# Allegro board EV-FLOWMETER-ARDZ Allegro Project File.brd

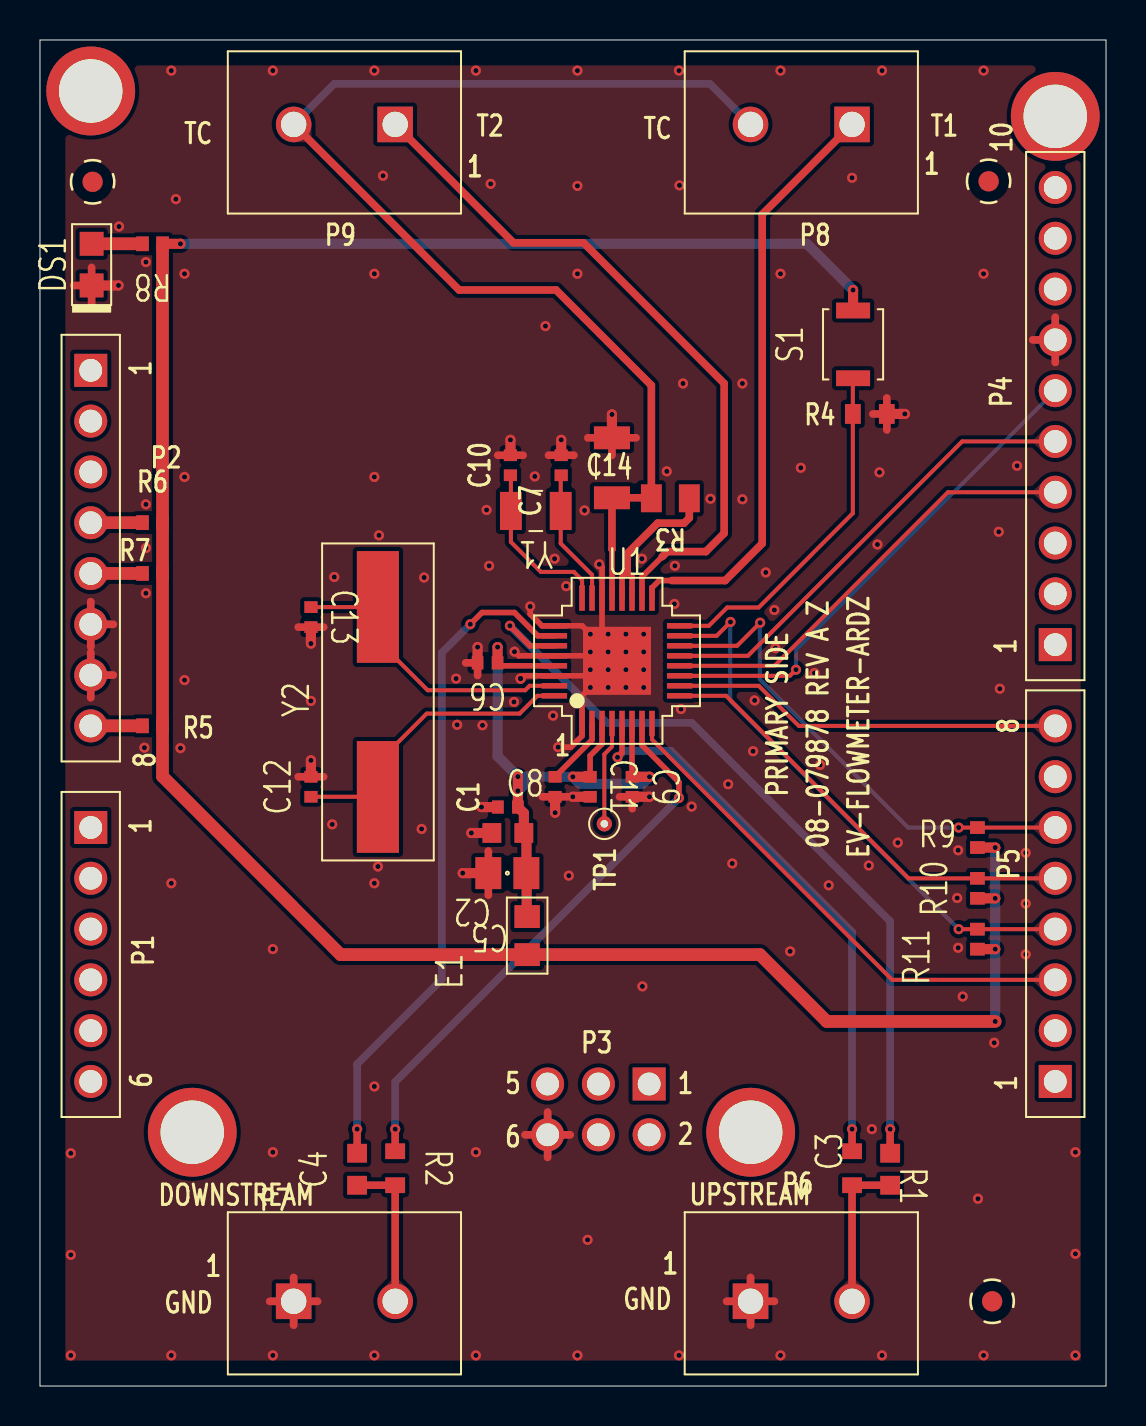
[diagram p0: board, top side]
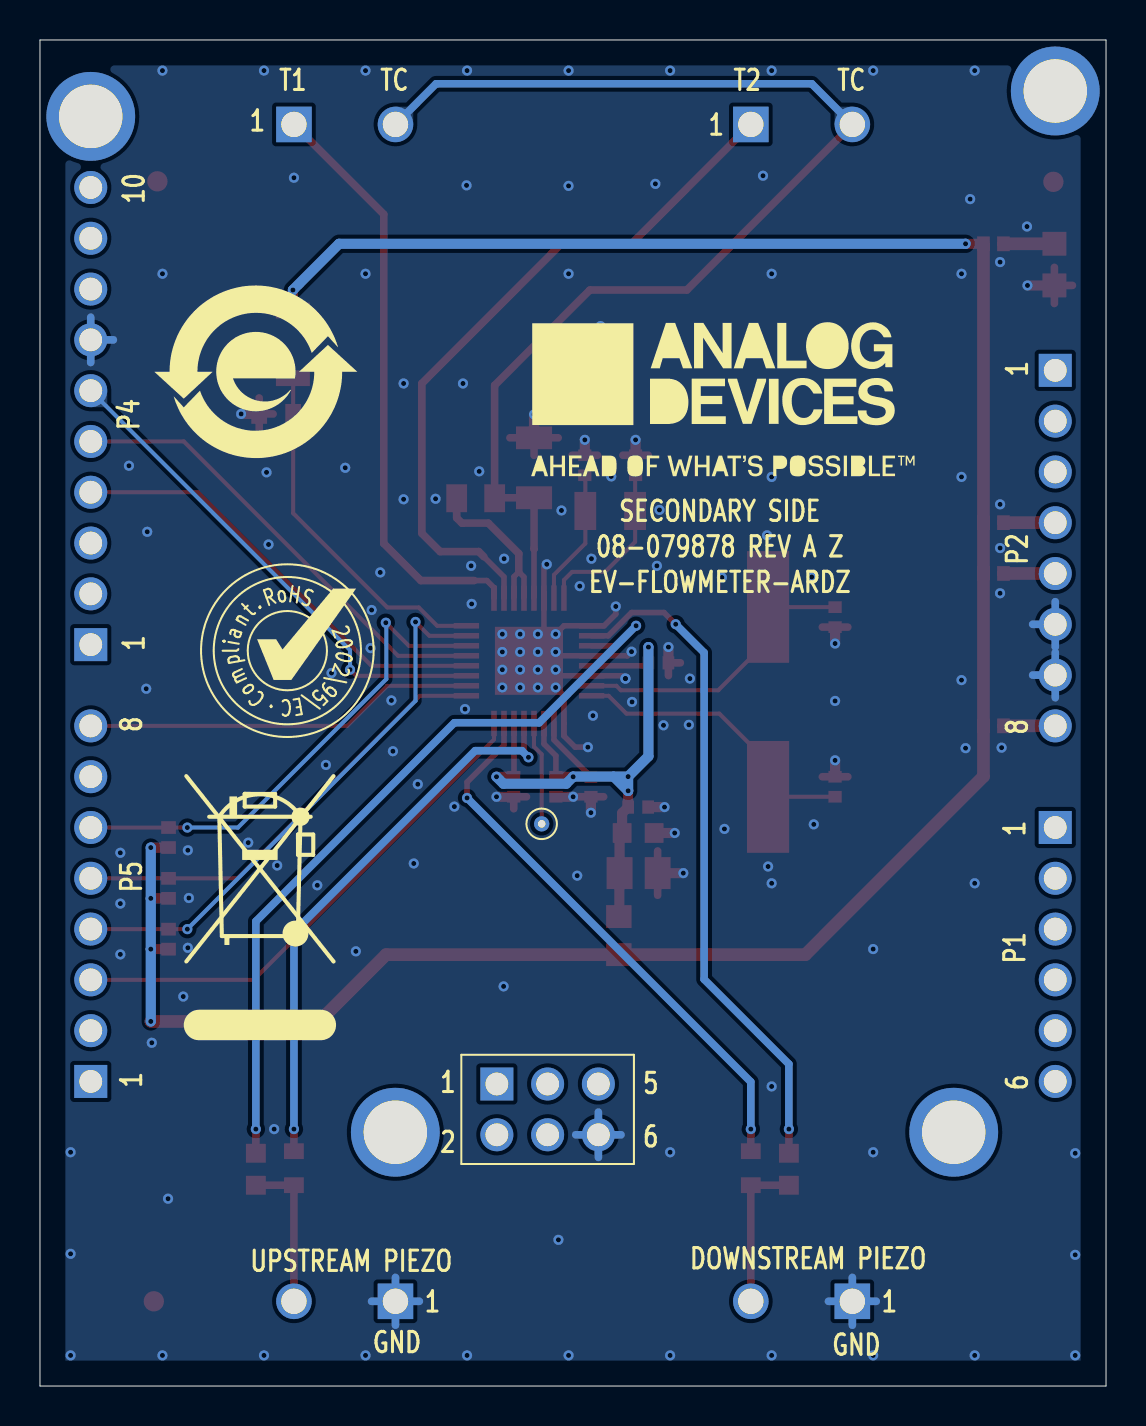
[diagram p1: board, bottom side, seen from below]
Outline 53.34 x 67.31 mm; copper layers: TOP, L2_GND, L3_GND, BOTTOM. Coordinates in mm from the lower left corner of the outline.
Outline path: 0,67.31 53.34,67.31 53.34,0 0,0 0,67.31

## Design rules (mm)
constraint set DEFAULT: min track width 0.203

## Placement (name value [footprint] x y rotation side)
C1  0.1uF  [C0402]  23.41 28.95 180 top
C2  2.2uF  [C0603]  23.41 27.65 180 top
C3  1000pF  [C0603]  42.54 10.84 90 top
C4  1000pF  [C0603]  15.87 10.84 90 top
C5  22UF  [C0805H60]  23.39 25.65 180 top
C6  0.1uF  [C0402]  22.4 36.16 180 top
C7  12pF  [C0402]  26.08 46.04 90 top
C8  0.1uF  [C0402]  25.77 29.97 90 top
C9  0.1uF  [C0402]  29.63 29.97 270 top
C10  12pF  [C0402]  23.54 46.04 90 top
C11  0.1uF  [C0402]  27.53 29.97 270 top
C12  12pF  [C0402]  13.56 29.97 90 top
C13  12pF  [C0402]  13.56 38.45 270 top
C14  0.1uF  [C1206]  28.62 45.92 90 top
DS1  SML-LXT0805YW-TR  [LXT0805]  2.58 56.08 90 top
E1  600OHM  [L0805H50]  24.38 22.52 90 top
NOREF  -  []  -14.58 90.73 0 top
NOREF#2  -  []  -30.49 -89.69 0 top
NOREF#3  -  [unnamed#2]  47.64 4.24 0 top
NOREF#4  -  [unnamed#2]  50.8 63.49 0 top
NOREF#5  -  []  -35.57 -94.77 0 top
NOREF#6  -  []  26.17 77.98 0 top
NOREF#7  -  []  -35.57 -94.77 0 top
NOREF#8  -  []  111.55 230.7 0 top
NOREF#9  -  [unnamed#2]  2.63 60.22 0 top
NOREF#10  -  []  -30.49 -89.69 0 top
NOREF#11  -  [unnamed#2]  35.56 12.69 0 top
NOREF#12  -  []  0 67.31 0 top
NOREF#13  -  [unnamed#2]  47.47 60.24 0 top
NOREF#14  -  []  100.54 -20.38 0 top
NOREF#15  -  []  53.34 0 90 top
NOREF#16  -  [unnamed#2]  2.54 64.76 0 top
NOREF#17  -  [unnamed#2]  7.62 12.69 0 top
NOREF#18  -  []  -35.57 -94.77 0 top
NOREF#19  -  []  19.14 49.32 180 bottom
NOREF#20  -  []  33.06 34.18 180 bottom
NOREF#21  -  []  40.96 36.77 180 bottom
NOREF#22  -  []  42.54 50.72 180 bottom
P1  SSQ-106-03-G-S  [CNSAMTECSSQ-106-XX-X-S]  2.54 27.93 270 top
P2  SSQ-108-03-G-S  [CNSAMTECSSQ-108-XX-X-S]  2.54 50.79 270 top
P3  SSQ-103-03-G-D  [CNSAMTECSSQ-103-XX-X-D]  30.48 15.1 180 bottom
P4  SSQ-110-03-G-S  [CNSAMTECSSQ-110-XX-X-S]  50.8 37.07 90 top
P5  SSQ-108-03-G-S  [CNSAMTECSSQ-108-XX-X-S]  50.8 15.23 90 top
P6  OSTTC022162  [CNHDR1X2H406]  35.55 4.24 0 top
P7  OSTTC022162  [CNHDR1X2H406]  12.69 4.24 0 top
P8  OSTTC022162  [CNHDR1X2H406]  40.63 63.09 180 top
P9  OSTTC022162  [CNHDR1X2H406]  17.77 63.09 180 top
R1  330  [R0603]  40.63 10.89 270 top
R2  330  [R0603]  17.77 10.89 270 top
R3  1K  [R0805]  31.54 44.39 180 top
R4  10MEG  [R0603]  41.52 48.61 0 top
R5  0  [R0402]  5.63 33.01 0 top
R6  0  [R0402]  5.63 43.17 0 top
R7  0  [R0402]  5.63 40.63 0 top
R8  470  [R0402]  5.63 57.12 180 top
R9  10K  [R0402]  46.91 27.43 90 top
R10  10K  [R0402]  46.91 24.89 90 top
R11  10K  [R0402]  46.91 22.35 90 top
S1  B3U-1000P  [SWSML118W98H69]  40.68 52.09 90 top
TP1  TESTPAD  [TPC30D15]  28.24 28.11 90 top
U1  MAX35101EHJ+  [QFP32_5X5_PAD3_4X3_4]  28.87 36.27 0 top
Y1  32.768KHZ  [YSML126W59H35]  24.81 43.76 180 top
Y2  4MEGHZ  [YSML450W190H160]  16.91 34.21 90 top

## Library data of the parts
C1 C6 C8 C9 C11 = CAP: User Part Number: UPN; Tolerance: 10; alternate symbols: (C0402); part number: CAP_SM-0.1UF,50V,10,E025746,C0402; tolerance: 10
C2 = CAP: User Part Number: UPN; Tolerance: 10; alternate symbols: (C0603); part number: CAP_SM-2.2UF,10V,10,E015288,C0603; tolerance: 10
C3 C4 = CAP: User Part Number: UPN; Tolerance: 1; alternate symbols: (C0603); part number: CAP_SM-1000PF,50V,1,E024659,C0603; tolerance: 1
C5 = CAP: Tolerance: 20; User Part Number: UPN; alternate symbols: (C0805H60); part number: CAP_SM-22UF,10V,20,E059803,C0805H60; tolerance: 20
C7 C10 C12 C13 = CAP: User Part Number: UPN; Tolerance: 5; alternate symbols: (C0402); part number: CAP_SM-12PF,50V,5,E033360,C0402; tolerance: 5
C14 = CAP: User Part Number: UPN; Tolerance: 2; alternate symbols: (C1206); part number: CAP_SM-0.1UF,25V,2,E012519,C1206; tolerance: 2
DS1 = DIOLED: Tolerance: N/A; User Part Number: UPN; alternate symbols: (LXT0805); part number: DIOLED_SM-SML-LXT0805YW-TR,N/A,N/A,E005351,LXT0805; tolerance: N/A
E1 = FERRITE: Tolerance: 25; User Part Number: UPN; alternate symbols: (L0805H50); part number: FERRITE_SM-600OHM,25,E013538,L0805H50; tolerance: 25
P1 = CN6P: User Part Number: UPN; Tolerance: N/A; alternate symbols: (CNSAMTECSSQ-106-XX-X-S); part number: CN6P_TH-SSQ-106-03-G-S,E020477,CNSAMTECSSQ-106-XX-X-S; tolerance: N/A
P2 P5 = CN8P_A: User Part Number: UPN; Tolerance: N/A; alternate symbols: (CNSAMTECSSQ-108-XX-X-S); part number: CN8P_A_TH-SSQ-108-03-G-S,E020478,CNSAMTECSSQ-108-XX-X-S; tolerance: N/A
P3 = CN6P_ODD_EVEN: User Part Number: UPN; Tolerance: N/A; alternate symbols: (CNSAMTECSSQ-103-XX-X-D); part number: CN6P_ODD_EVEN_TH-SSQ-103-03-G-D,E020488,CNSAMTECSSQ-103-XX-X-D; tolerance: N/A
P4 = CN10P: User Part Number: UPN; Tolerance: N/A; alternate symbols: (CNSAMTECSSQ-110-XX-X-S); part number: CN10P_TH-SSQ-110-03-G-S,E020479,CNSAMTECSSQ-110-XX-X-S; tolerance: N/A
P6-P9 = CN2P: User Part Number: UPN; Tolerance: N/A; alternate symbols: (CNHDR1X2H406); part number: CN2P_TH-OSTTC022162,E016936,CNHDR1X2H406; tolerance: N/A
R1 R2 = RES: User Part Number: UPN; Tolerance: 1; alternate symbols: (R0603); part number: RES_SM-330,E054284,1/10W,1,R0603; tolerance: 1
R3 = RES: User Part Number: UPN; Tolerance: 0.1; alternate symbols: (R0805); part number: RES_SM-1K,E003811,1/8W,0.1,R0805; tolerance: 0.1
R4 = RES: User Part Number: UPN; Tolerance: 1; alternate symbols: (R0603); part number: RES_SM-10MEG,E055939,1/10W,1,R0603; tolerance: 1
R5-R7 = RES: User Part Number: UPN; Tolerance: JUMPER; alternate symbols: (R0402); part number: RES_SM-0,E003438,1/10W,JUMPER,R0402; tolerance: JUMPER
R8 = RES: User Part Number: UPN; Tolerance: 1; alternate symbols: (R0402); part number: RES_SM-470,E014032,1/16W,1,R0402; tolerance: 1
R9-R11 = RES: User Part Number: UPN; Tolerance: 1; alternate symbols: (R0402); part number: RES_SM-10K,E003751,1/10W,1,R0402; tolerance: 1
S1 = SWSPST2PIN_V2: Tolerance: N/A; User Part Number: UPN; alternate symbols: (SWSML118W98H69); part number: SWSPST2PIN_V2_SM-B3U-1000P,E016303,SWSML118W98H69; tolerance: N/A
TP1 = NCTESTPAD: Tolerance: N/A; User Part Number: UPN; alternate symbols: (TPC30D15); part number: NCTESTPAD_TH-TESTPAD,E013464,TPC30D15; tolerance: N/A
U1 = ADMAX35101: User Part Number: UPN; Tolerance: N/A; alternate symbols: (QFP32_5X5_PAD3_4X3_4); part number: ADMAX35101_SM-MAX35101EHJ+,E062766,QFP32_5X5_PAD3_4X3_4; tolerance: N/A
Y1 = XTAL: User Part Number: UPN; Tolerance: N/A; alternate symbols: (YSML126W59H35); part number: XTAL_SM-32.768KHZ,E062517,YSML126W59H35; tolerance: N/A
Y2 = XTAL: Tolerance: 30PPM; User Part Number: UPN; alternate symbols: (YSML450W190H160); part number: XTAL_SM-4MEGHZ,E060056,YSML450W190H160; tolerance: 30PPM

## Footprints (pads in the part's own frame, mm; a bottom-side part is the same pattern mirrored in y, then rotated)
C0402
  rect 0.584x0.66 smd: 1(-0.5,0) 2(0.5,0)
C0603
  rect 0.94x0.991 smd: 1(-0.8,0) 2(0.8,0)
C0805H60
  rect 1.295x1.6 smd: 1(-0.953,0) 2(0.953,0)
C1206
  rect 1.143x1.803 smd: 1(-1.5,0) 2(1.5,0)
CNHDR1X2H406
  rect 1.778x1.778 hole 1.27: 1(0,0)
  round 1.778 hole 1.27: 2(5.08,0)
CNSAMTECSSQ-103-XX-X-D
  rect 1.651x1.651 hole 1.143: 1(0,0)
  round 1.651 hole 1.143: 2(0,-2.54) 3(2.54,0) 4(2.54,-2.54) 5(5.08,0) 6(5.08,-2.54)
CNSAMTECSSQ-106-XX-X-S
  rect 1.651x1.651 hole 1.143: 1(0,0)
  round 1.651 hole 1.143: 2(2.54,0) 3(5.08,0) 4(7.62,0) 5(10.16,0) 6(12.7,0)
CNSAMTECSSQ-108-XX-X-S
  rect 1.651x1.651 hole 1.143: 1(0,0)
  round 1.651 hole 1.143: 2(2.54,0) 3(5.08,0) 4(7.62,0) 5(10.16,0) 6(12.7,0) 7(15.24,0) 8(17.78,0)
CNSAMTECSSQ-110-XX-X-S
  rect 1.651x1.651 hole 1.143: 1(0,0)
  round 1.651 hole 1.143: 2(2.54,0) 3(5.08,0) 4(7.62,0) 5(10.16,0) 6(12.7,0) 7(15.24,0) 8(17.78,0) 9(20.32,0) 10(22.86,0)
L0805H50
  rect 1.143x1.27 smd: 1(-0.953,0) 2(0.953,0)
LXT0805
  rect 1.194x1.194 smd: A(1.041,0) C(-1.041,0)
QFP32_5X5_PAD3_4X3_4
  rect 0.279x1.27 smd: 1(-1.75,-3.134) 2(-1.25,-3.134) 3(-0.75,-3.134) 4(-0.25,-3.134) 5(0.25,-3.134) 6(0.75,-3.134) 7(1.25,-3.134) 8(1.75,-3.134) 17(1.75,3.134) 18(1.25,3.134) 19(0.75,3.134) 20(0.25,3.134) 21(-0.25,3.134) 22(-0.75,3.134) 23(-1.25,3.134) 24(-1.75,3.134)
  rect 1.27x0.279 smd: 9(3.134,-1.75) 10(3.134,-1.25) 11(3.134,-0.75) 12(3.134,-0.25) 13(3.134,0.25) 14(3.134,0.75) 15(3.134,1.25) 16(3.134,1.75) 25(-3.134,1.75) 26(-3.134,1.25) 27(-3.134,0.75) 28(-3.134,0.25) 29(-3.134,-0.25) 30(-3.134,-0.75) 31(-3.134,-1.25) 32(-3.134,-1.75)
  rect 3.404x3.404 smd: PAD(0,0)
R0402
  rect 0.635x0.737 smd: 1(-0.5,0) 2(0.5,0)
R0603
  rect 0.787x0.991 smd: 1(-0.85,0) 2(0.85,0)
R0805
  rect 1.041x1.397 smd: 1(-0.95,0) 2(0.95,0)
SWSML118W98H69
  rect 0.787x1.702 smd: 1(-1.694,0) 2(1.694,0)
TPC30D15
  round 0.762 hole 0.381: 1(0,0)
unnamed#2
  round 1.016 smd: (0,0)
YSML126W59H35
  rect 1.092x1.905 smd: 1(-1.246,0) 2(1.246,0)
YSML450W190H160
  rect 5.588x2.108 smd: 1(-4.75,0) 2(4.75,0)

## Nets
GND: C1.2(N2) C2.2(N2) C5.2(N2) C6.2(N2) C7.2(N2) C8.1 C9.2(N2) C10.2(N2) C11.2(N2) C12.2(N2) C13.2(N2) C14.2(N2) DS1.C P2.6 P2.7 P3.6(N6) P4.7 P6.1 P7.1 R4.2(N2) U1.1 U1.22 U1.25 U1.28 U1.30 U1.PAD
32KX0: C7.1 U1.23 Y1.1
32KX1: C10.1 U1.24 Y1.2(N2)
ARD_3V3: E1.1 R5.2(N2) R6.2(N2) R7.2(N2) R8.1 R9.1 R10.1 R11.1 S1.2(B)
ARD_CS: P5.8(N8) U1.10
ARD_MISO: P4.5 U1.13
ARD_MOSI: P4.4 U1.12
ARD_SCK: P4.6 U1.11
CMP_OUTPUT/UP_DN: P5.3 U1.8
CSW: R4.1 S1.1 U1.16
INT_N: P5.5 R10.2(N2) U1.9
LAUNCH_DN: R1.1 U1.5
LAUNCH_UP: R2.1 U1.7
RST_N: P5.6 R9.2(N2) U1.14
STOP_DN: C4.2(N2) U1.26
STOP_UP: C3.2(N2) U1.27
T1: P8.1 U1.17
T2: P9.1 U1.18
TC: C14.1 P8.2(N2) P9.2(N2) R3.2(N2) U1.21
UNNAMED_2_ADMAX35101_I1_32KOUT: TP1.1(N1) U1.4
UNNAMED_2_ADMAX35101_I1_BYPASS: C8.2(N2) U1.2
UNNAMED_2_ADMAX35101_I1_T3: R3.1 U1.19 U1.20
UNNAMED_2_CAP_I17_N1: C1.1 C2.1 C5.1 C6.1 C9.1 C11.1 E1.2(N2) U1.3 U1.6 U1.29
UNNAMED_2_CAP_I55_N1: C3.1 P6.2(N2) R1.2(N2)
UNNAMED_2_CAP_I59_N1: C4.1 P7.2(N2) R2.2(N2)
UNNAMED_2_CN8PA_I23_N4: P2.4 R6.1
UNNAMED_2_CN8PA_I23_N5: P2.5 R7.1
UNNAMED_2_CN8PA_I23_N8: P2.8(N8) R5.1
UNNAMED_2_DIOLED_I71_P: DS1.A(P) R8.2(N2)
WDO_N: P5.4 R11.2(N2) U1.15
X1: C12.1 U1.32 Y2.1
X2: C13.1 U1.31(X2) Y2.2(N2)

Pads without a net: P1 1 2 3 4 5 6; P2 1 2 3; P3 1 2 3 4 5; P4 1 2 3 8 9 10; P5 1 2 7

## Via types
v1: diameter 0.508, hole 0.254, TOP to BOTTOM, 172 vias

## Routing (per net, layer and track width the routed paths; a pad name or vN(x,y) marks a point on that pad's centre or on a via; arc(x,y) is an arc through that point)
GND: length 153.4
  TOP w0.279: v1(27.54,34.93) 27.12,34.52 U1.1 27.12,32.51 26.56,31.95 v1(25.93,31.95) ; v1(27.98,41.09) 28.12,40.95 U1.22 28.12,37.02 ; 28.62,36.52 U1.28 23.95,36.52 v1(23.74,36.72) ; 28.62,36.52 v1(28.43,36.71) 28.12,37.02 ; 28.62,36.52 U1.PAD v1(28.43,35.82) 28.12,35.52 U1.30 24.19,35.52 v1(24.05,35.38) ; v1(24.53,38.98) 24.53,38.6 25.12,38.02 U1.25 27.12,38.02 v1(27.54,37.6) 28.12,37.02
  TOP w0.381: 41.67,48.61 R4.2 ; R4.2 42.37,49.41 ; R4.2 42.37,47.81 ; 24.27,12.56 25.4,12.56 ; 25.4,12.56 26.53,12.56 ; 25.4,12.56 25.4,11.43 ; 25.4,12.56 25.4,13.69 ; 26.71,46.54 C7.2 25.44,46.54 ; 50.8,51.18 P4.7 ; P4.7 50.8,53.44 ; P4.7 49.67,52.31 ; DS1.C 2.58,55.94 ; DS1.C 2.58,54.13 ; DS1.C 1.68,55.04 ; 24.17,46.54 C10.2 22.9,46.54 ; 28.62,46.54 C14.2 ; C14.2 29.83,47.42 ; C14.2 27.41,47.42 ; 21.9,35.53 C6.2 21.3,36.16 ; P6.1 35.55,5.43 ; P6.1 35.55,3.04 ; P6.1 34.36,4.24 ; P6.1 36.75,4.24 ; 14.19,30.47 C12.2 12.92,30.47 ; 14.19,37.95 C13.2 12.92,37.95 ; P2.6 2.54,39.22 ; P2.6 3.67,38.09 ; P2.6 2.54,36.96 ; 22.43,26.75 C5.2 22.43,24.54 ; P7.1 13.89,4.24 ; P7.1 12.69,5.43 ; P7.1 12.69,3.04 ; P7.1 11.5,4.24 ; P2.7 3.67,35.55 ; P2.7 2.54,36.68 ; P2.7 2.54,34.42 ; 29.63,28.87 C9.2 29,29.47 ; 25.14,29.47 C8.1 26.41,29.47
  TOP w0.508: C7.2 v1(26.08,47.31) ; C5.2 v1(21.15,25.65) ; v1(43.27,48.61) R4.2 ; C11.2 v1(26.66,29.47) ; C8.1 v1(25.77,28.67) ; C1.2 v1(22.09,28.95) ; C9.2 v1(30.5,29.47) ; C14.2 v1(28.62,48.58) ; C13.2 v1(13.56,37.13) ; C2.2 v1(21.58,27.65) ; C6.2 v1(21.9,36.95) ; C10.2 v1(23.54,47.31) ; DS1.C v1(3.93,55.04) ; C12.2 v1(13.56,31.29)
  L2_GND w0.381: 12.69,3.04 P7.1 ; P7.1 13.89,4.24 ; P7.1 12.69,5.43 ; P7.1 11.5,4.24 ; P2.7 2.54,36.68 ; P2.7 2.54,34.42 ; P2.7 3.67,35.55 ; P2.6 2.54,39.22 ; P2.6 3.67,38.09 ; P2.6 2.54,36.96 ; 50.8,51.18 P4.7 ; P4.7 49.67,52.31 ; P4.7 50.8,53.44 ; 25.4,12.56 26.53,12.56 ; 25.4,12.56 25.4,11.43 ; 25.4,12.56 24.27,12.56 ; 25.4,12.56 25.4,13.69 ; P6.1 35.55,5.43 ; P6.1 36.75,4.24 ; P6.1 34.36,4.24 ; P6.1 35.55,3.04
  L3_GND w0.381: 11.5,4.24 P7.1 ; P7.1 13.89,4.24 ; P7.1 12.69,5.43 ; P7.1 12.69,3.04 ; P2.7 3.67,35.55 ; P2.7 2.54,34.42 ; P2.7 2.54,36.68 ; 2.54,36.96 P2.6 ; P2.6 2.54,39.22 ; P2.6 3.67,38.09 ; 35.55,3.04 P6.1 ; P6.1 35.55,5.43 ; P6.1 34.36,4.24 ; P6.1 36.75,4.24 ; 24.27,12.56 25.4,12.56 ; 25.4,12.56 25.4,13.69 ; 25.4,12.56 25.4,11.43 ; 25.4,12.56 26.53,12.56 ; P4.7 50.8,53.44 ; P4.7 50.8,51.18 ; P4.7 49.67,52.31
  BOTTOM w0.381: P4.7 50.8,53.44 ; P4.7 49.67,52.31 ; P4.7 50.8,51.18 ; 34.36,4.24 P6.1 ; P6.1 35.55,5.43 ; P6.1 36.75,4.24 ; P6.1 35.55,3.04 ; 2.54,34.42 P2.7 ; P2.7 3.67,35.55 ; P2.7 2.54,36.68 ; P7.1 13.89,4.24 ; P7.1 12.69,5.43 ; P7.1 12.69,3.04 ; P7.1 11.5,4.24 ; 2.54,36.96 P2.6 ; P2.6 3.67,38.09 ; P2.6 2.54,39.22 ; 25.4,11.43 25.4,12.56 ; 25.4,12.56 25.4,13.69 ; 25.4,12.56 26.53,12.56 ; 25.4,12.56 24.27,12.56
  vias: v1(1.54,11.64) v1(1.54,6.56) v1(1.54,1.53) v1(3.96,57.98) v1(5.23,31.92) v1(5.3,56.2) v1(5.3,44.09) v1(5.3,41.9) v1(5.3,39.64) v1(6.57,65.78) v1(6.57,25.14) v1(6.57,1.53) v1(6.8,59.35) v1(7.03,31.9) v1(7.23,55.62) v1(7.23,45.46) v1(7.23,35.3) v1(11.65,65.78) v1(11.65,21.85) v1(11.65,11.69) v1(11.65,1.53) v1(13.56,34.26) v1(14.62,28.09) v1(14.73,40.46) v1(16.73,65.78) v1(16.73,55.62) v1(16.73,45.46) v1(16.73,25.14) v1(16.73,14.98) v1(16.73,1.53) v1(16.96,42.54) v1(16.91,25.98) v1(17.16,60.52) v1(19.09,27.86) v1(19.22,40.43) v1(20.82,35.38) v1(20.87,33.06) v1(21.81,65.78) v1(21.81,11.69) v1(21.81,1.53) v1(22.14,33.04) v1(22.35,43.81) v1(22.55,60.12) v1(22.47,41.01) v1(23.72,34.21) v1(24.76,45.49) v1(25.29,53) v1(25.75,41.37) v1(25.67,33.52) v1(26.33,40) v1(26.46,25.52) v1(26.89,65.78) v1(26.89,60.01) v1(26.89,55.62) v1(26.89,1.53) v1(27.25,43.78) v1(27.4,7.31) v1(27.54,36.71) v1(27.54,35.82) v1(28.43,37.6) v1(28.43,34.93) v1(29.32,37.6) v1(29.32,36.71) v1(29.32,35.82) v1(29.32,34.93) v1(30.12,41.37) v1(30.14,19.98) v1(30.21,37.6) v1(30.21,36.71) v1(30.21,35.82) v1(30.21,34.93) v1(31.36,45.74) v1(31.77,41.01) v1(31.74,39.11) v1(31.97,65.78) v1(32,60.04) v1(31.97,1.53) v1(32.07,33.85) v1(32.17,50.13) v1(32.61,28.98) v1(33.55,44.37) v1(34.44,30.09) v1(34.64,26.13) v1(35.15,50.13) v1(35.15,44.34) v1(35.76,34.28) v1(35.68,31.74) v1(36.32,40.68) v1(36.75,38.81) v1(36.8,36.9) v1(37.05,65.78) v1(37.05,55.62) v1(37.05,1.53) v1(37.53,21.74) v1(38.07,45.92) v1(38.75,35.66) v1(39.03,31.06) v1(39.46,25.04) v1(40.63,60.42) v1(41.47,26.03) v1(41.62,12.85) v1(41.9,42.08) v1(42,45.69) v1(42.13,65.78) v1(42.13,1.53) v1(42.92,27.17) v1(45.94,26.79) v1(45.89,24.4) v1(45.94,21.91) v1(46.17,19.48) v1(46.93,9.37) v1(47.21,65.78) v1(47.21,55.62) v1(47.21,1.53) v1(47.75,17.16) v1(47.97,42.72) v1(48.02,34.87) v1(48.89,46.02) v1(49.32,26.66) v1(49.32,24.12) v1(49.32,21.58) v1(51.81,11.69) v1(51.81,6.61) v1(51.81,1.53)
32KX0: length 6.8
  TOP w0.203: U1.23 27.62,40.56 26.06,42.13 Y1.1 26.06,45.52 C7.1
32KX1: length 8.6
  TOP w0.203: C10.1 23.56,45.52 Y1.2 23.56,42.21 25.06,40.71 26.71,40.71 27.12,40.3 U1.24
ARD_3V3: length 121.3
  TOP w0.508: R10.1 v1(47.8,24.39) ; R8.1 v1(7.03,57.12) ; R9.1 v1(47.8,26.93) ; R11.1 v1(47.8,21.85) ; S1.2 v1(40.68,54.81)
  TOP w0.635: R8.1 R6.2 R7.2 R5.2 6.13,30.48 15.04,21.57 E1.1 36.02,21.57 39.36,18.23 v1(47.8,18.23)
  BOTTOM w0.508: v1(47.8,18.23) v1(47.8,21.85) v1(47.8,24.39) v1(47.8,26.93) ; v1(7.03,57.12) 38.37,57.12 v1(40.68,54.81)
ARD_CS: length 19.6
  TOP w0.203: P5.8 37.97,33.01 35.96,35.02 U1.10
ARD_MISO: length 23.2
  TOP w0.203: U1.13 35.42,36.52 46.14,47.23 P4.5
ARD_MOSI: length 22.4
  TOP w0.203: P4.4 45.43,44.69 36.75,36.02 U1.12
ARD_SCK: length 25.3
  TOP w0.203: U1.11 37.52,35.52 v1(37.83,35.82)
  BOTTOM w0.203: v1(37.83,35.82) 37.83,36.8 P4.6
CMP_OUTPUT/UP_DN: length 26
  TOP w0.203: U1.8 30.62,32.33 42.64,20.31 P5.3
CSW: length 17.8
  TOP w0.203: S1.1 40.67,50.38 R4.1 40.67,43.64 35.96,38.93 34.38,38.93 33.47,38.02 U1.16
INT_N: length 22.6
  TOP w0.203: P5.5 50.8,25.39 R10.2 43.46,25.39 34.33,34.52 U1.9
LAUNCH_DN: length 28.4
  TOP w0.279: U1.5 29.12,31.66 v1(28.9,31.44)
  TOP w0.381: R1.1 v1(40.63,12.85)
  BOTTOM w0.381: v1(40.63,12.85) 40.63,22.7 31.57,31.77 29.23,31.77 v1(28.9,31.44)
LAUNCH_UP: length 28
  TOP w0.279: U1.7 30.12,32.04 31.97,30.19 v1(31.97,29.41)
  TOP w0.381: R2.1 v1(17.77,12.85)
  BOTTOM w0.381: v1(31.97,29.41) 17.77,15.21 v1(17.77,12.85)
RST_N: length 25.2
  TOP w0.203: v1(45.97,27.93) R9.2 50.8,27.93 P5.6 ; v1(36.04,38.17) 34.88,37.02 U1.14
  BOTTOM w0.203: v1(45.97,27.93) 43.44,27.93 36.01,35.35 36.01,38.14 v1(36.04,38.17)
STOP_DN: length 33.7
  TOP w0.279: U1.26 24.91,37.52 23.74,38.68 22.12,38.68 v1(21.53,38.09)
  TOP w0.381: C4.2 v1(15.87,12.85)
  BOTTOM w0.381: v1(15.87,12.85) 15.87,16.1 20.11,20.34 20.11,36.67 v1(21.53,38.09)
STOP_UP: length 39.4
  TOP w0.279: v1(23.51,38.02) 24.52,37.02 U1.27
  TOP w0.381: C3.2 v1(42.54,12.85)
  BOTTOM w0.381: v1(23.51,38.02) 28.36,33.17 32.61,33.17 42.54,23.23 v1(42.54,12.85)
T1: length 29.8
  TOP w0.279: 31.62,40.28 30.98,40.28 30.62,39.92 U1.17
  TOP w0.381: 31.62,40.28 34.28,40.28 36.14,42.13 36.14,58.59 P8.1
T2: length 35.4
  TOP w0.279: U1.18 30.12,40.46 31.13,41.47
  TOP w0.381: 31.13,41.47 31.39,41.73 33.32,41.73 34.23,42.64 34.23,50.13 27.2,57.17 23.69,57.17 P9.1
TC: length 60.5
  TOP w0.279: 28.62,41.85 U1.21
  TOP w0.381: 28.62,41.85 28.62,41.86 C14.1 30.57,44.42 R3.2 30.59,50.04 25.82,54.81 20.97,54.81 P9.2
  BOTTOM w0.381: P9.2 14.73,65.12 33.52,65.12 P8.2
UNNAMED_2_ADMAX35101_I1_32KOUT: length 5.2
  TOP w0.203: TP1.1 28.24,31.59 28.62,31.98 U1.4
UNNAMED_2_ADMAX35101_I1_BYPASS: length 3.4
  TOP w0.279: U1.2 27.62,32.31 C8.2
UNNAMED_2_ADMAX35101_I1_T3: length 8.6
  TOP w0.279: U1.19 29.62,40.47 29.38,40.71 29.12,40.45 U1.20
  TOP w0.381: 29.38,40.71 29.38,41.62 30.9,43.15 32.23,43.15 32.49,43.41 R3.1
UNNAMED_2_CAP_I17_N1: length 33.7
  TOP w0.279: C6.1 23.04,36.02 U1.29 ; U1.6 29.62,30.48 C9.1 ; C11.1 27.53,31.52 28.12,32.11 U1.3
  TOP w0.508: E1.2 24.35,23.5 24.35,25.64 C5.1 24.34,27.53 C2.1 24.21,28.65 C1.1 v1(23.91,29.76) v1(23.91,30.47) ; C6.1 v1(22.9,36.95) ; C9.1 v1(30.5,30.47) ; C11.1 v1(26.66,30.47)
  BOTTOM w0.508: 24.63,30.47 23.92,29.76 v1(23.91,29.76) v1(23.91,30.47) ; 24.63,30.47 26.66,30.47 v1(26.66,30.47) 27.01,30.12 30.15,30.12 v1(30.5,30.47) ; 24.63,30.47 v1(23.91,30.47) ; v1(23.91,30.47) 22.9,31.49 v1(22.9,36.95)
UNNAMED_2_CAP_I55_N1: length 7.7
  TOP w0.381: P6.2 R1.2 C3.1
UNNAMED_2_CAP_I59_N1: length 7.7
  TOP w0.381: P7.2 R2.2 15.87,10.04 C4.1
UNNAMED_2_CN8PA_I23_N4: length 2.6
  TOP w0.635: R6.1 2.54,43.17 P2.4
UNNAMED_2_CN8PA_I23_N5: length 2.6
  TOP w0.635: R7.1 2.54,40.63 P2.5
UNNAMED_2_CN8PA_I23_N8: length 2.6
  TOP w0.635: R5.1 2.54,33.01 P2.8
UNNAMED_2_DIOLED_I71_P: length 2.5
  TOP w0.635: DS1.A R8.2
WDO_N: length 27.8
  TOP w0.203: P5.4 50.8,22.85 R11.2 v1(45.97,22.85) ; v1(34.55,38.21) 33.86,37.52 U1.15
  BOTTOM w0.203: v1(34.55,38.21) 34.55,34.26 v1(45.97,22.85)
X1: length 15.3
  TOP w0.203: C12.1 16.9,29.47 Y2.1 16.91,31.19 19.35,33.62 24,33.62 24.89,34.52 U1.32
X2: length 15
  TOP w0.203: U1.31 24.5,35.02 24.28,34.79 19.4,34.79 16.91,37.28 Y2.2 16.9,38.95 C13.1

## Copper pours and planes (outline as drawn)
GND on TOP: 1.27,66.04 52.07,66.04 52.07,1.27 1.27,1.27 ; 2 cut-outs
GND on BOTTOM, L2_GND, L3_GND: 1.27,66.04 52.07,66.04 52.07,1.27 1.27,1.27

Small or netless copper shapes (teardrops, artwork): 28 on TOP, 8 on BOTTOM

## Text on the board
Ref Des/Silkscreen Bottom: GND | TC | DOWNSTREAM PIEZO | T2 | SECONDARY SIDE | 08-079878 REV A Z | EV-FLOWMETER-ARDZ | 5 | 6 | UPSTREAM PIEZO | T1 | 1 | P2 | 8 | P1 | 10 | P5 | P4
User.Comments: COMPONENT KEEPOUT AREA | COMPONENTS GREATER THAN 1.5MM | 6.    THE FOLLOWING PARTS ARE DNI(DO NOT INSTALL): | DIRECTIVE 2002/95/EC). | B. P2 | C. P4 | D. P5 | WITH LEAD-FREE AND RoHS PCB ASSEMBLY STANDARDS (EU RoHS | 5.    DO NOT TRIM EXCESS PINS FOR THE FOLLOWING LOCATIONS | A. P1 | -R9 | -P3 | -R5,R7 | 4.    RoHS COMPLIANCE. ASSEMBLY VENDOR SHOULD ASSURE COMPLIANCE
Ref Des/Silkscreen Top: GND | TC | DOWNSTREAM | T2 | 5 | 6 | 1 | P3 | 2 | UPSTREAM | T1 | 8 | PRIMARY SIDE | 08-079878 REV A Z | EV-FLOWMETER-ARDZ | 10
DIMENSION: -0.50IN | 2.15IN | "0" | (REF) | -0.30IN | 1.80IN
PAGE_OUTLINE: EV-FLOWMETER-ARDZ
User.10: L2 Internal GND | 08-      -07
User.11: L3 Internal GND | 08-      -08
User.12: FAB NOTES REVISION: 2ND NOVEMBER 2022 | 8.   IMPEDANCE REQUIREMENTS: IF NO STACKUP IS DEFINED, THE VENDOR IS ALLOWED TO ADJUST THE DIELECTRIC | 13.  PLATING SPECIFICATION: | 9.   FILLET OPTIONS TO ENHANCE RELIABILITY AT PAD JUNCTIONS WHERE SPACING PERMITS. | 10.  THIEVING: | 11.  LAYER TO LAYER REGISTRATION SHALL BE WITHIN 0.003 INCHES. | 12.  DRILL SIZES ARE FINISHED HOLE SIZES. ALL HOLES SHALL BE LOCATED WITHIN 0.005 INCHES DTP,UNLESS SPECIFIED. | 14.  SURFACE FINISH: | 15.  SOLDERMASK: | 1.   DIMENSIONS ARE IN INCHES (EXCEPT WHERE NOTED). | ALL DOCUMENTS & SPECIFICATIONS REFERRED TO BELOW SHOULD BE THE LATEST REVISIONS. | 2.  BOARD MATERIAL:(USE CHECKED ITEMS) | 3.   ALL LAMINATES & BONDING MATERIALS SHOULD BE SELECTED FROM IPC-4101 OR IPC-4103,(TG>170 DEGC TD>300 DEGC) | 4.   REFER TO IPC-6010 SERIES, CLASS 2 FOR FABRICATION. | 5.   REFER TO LAMINATION DIAGRAM FOR OVERALL BOARD THICKNESS, TOLERANCE APPLIES AFTER ALL LAMINATION AND PLATING | 6.   BOW & TWIST NOT TO EXCEED 0.0075 INCHES (0.75%) PER LINEAR INCH AND SHOULD BE MEASURED PER IPC-TM-650, METHOD 2.4.22. | 7.   ACCEPTABILITY PER ADI SPECIFICATION TST00115. | 16.  APPLY SILKSCREEN TO BOTH SIDES USING A NON-CONDUCTIVE, EPOXY BASED INK PER ARTWORK. | ( ) FILLETS ALLOWED | (X) FILLETS NOT ALLOWED | ( ) VENDOR MAY ADD THIEVING TO COMPENSATE FOR LOW COPPER DENSITY AREAS MAINTAINING A MINIMUM | ( ) VENDOR MAY NOT ADD THIEVING TO COMPENSATE FOR LOW COPPER DENSITY AREAS. | (X) LPI | ( ) OTHER_________ | COLOR | ( ) GREEN | (X) OTHER_________ | (X) WHITE | ( ) OTHER | HINDER PROPER SOLDER WICKING. BARREL RELIEF ON SOLDERMASK ALLOWED IN UNFILLED VIA IN PAD HOLES. | (X) REFER TO LAMINATION DIAGRAM FOR FINISHED COPPER WEIGHT/THICKNESS REQUIRMENTS | (X) IMMERSION GOLD (ENIG) 1.58-3.94 MICRO INCHES OVER 118-236 MICRO INCHES MIN. OF ELECTROLESS NICKEL PER IPC-4552 | ( ) OSP (ORGANIC SOLDERABILITY PRESERVATIVE) | ( ) IMMERSION SILVER | ( ) SOFT WIRE BONDABLE GOLD 30-50 MICRO INCHES OF SOFT WIRE | ( ) EDGE CONNECTOR FINGERS ARE TO BE PLATED WITH 100 MICRO-INCHES(.0001") OF LOW STRESS | ( ) OTHER: | THICKNESS & TRACE WIDTHS TO MEET THE IMPEDANCE REQUIREMENT. IF SPECIFIED, THE VENDOR MUST | TRACE WIDTH & SPACING THAT IMPACT THE REQUIREMENTS MUST HAVE WRITTEN APPROVAL FROM ADI. | MINIMUM BARREL PLATING OF 0.001 INCHES. PLATED HOLES SHALL NOT BE ROUGH OR IRREGULAR SO AS TO | SOLDERMASK OVER BARE COPPER OR BARE GOLD (BOTH SIDES) TO MEET IPC-SM-840. | IF PRESENT,DO NOT MODIFY SOLDERMASK DEFINED PADS (MASK OPENINGS LESS THAN COPPER PAD) WITHOUT APPROVAL. | MEET THE REQUIREMENTS LISTED IN THE IMPEDANCE TABLE. ANY ADJUSTMENT MADE TO THE DEFINED STACKUP, | PROCESSES. FINISHED THICKNESS MEASURED FROM TOP COPPER TO BOTTOM COPPER. | (X)  ISOLA 370HR OR EQUIVALENT | ( )  ISOLA-FR408HR OR EQUIVALENT | ( )  ISOLA IS410 | ( )  MEGTRON 6 | ( )  NELCO-4000-13 | ( )  ROGERS 4350B | ( ) ROGERS 3003 | ( ) ARLON 85N | ( ) EM370D | ( )  OTHER ________________________ | X | UL FLAMMABILITY RATING 94V-0. BOARD MATERIAL & CONSTRUCTION SHALL MEET THE REQUIREMENTS OF UL796/UL796F. | BONDABLE GOLD OVER 100-150 MICRO INCHES OF NICKEL | NICKEL UNDER 30 MICRO-INCHES (.0003') OF GOLD | 0.100 INCH CLEARANCE FROM ALL COPPER FEATURES, | THE STARTING COPPER WEIGHT/THICKNESS CAN VARY AS LONG AS THE FINISHED COPPER | WEIGHT/THICKNESS IS NOT LESS THAN THE SPECIFIED VALUE. | UNLESS OTHERWISE SPECIFIED | BLUE | HOMOGENOUS MATERIALS IN THIS BOARD SHALL BE COMPLAINT WITH THE EU DIRECTIVE 2002/95/EC | WORKMANSHIP SHALL CONFORM TO IPC-A-600, CLASS 2. | 21.  INTENTIONAL SHORTS: | 17.  FINAL ELECTRICAL TEST TO BE PERFORMED USING PROVIDED IPC-D-356A NETLIST OR ODB++ FORMAT FILE. | 22.  PEMNUTS: | 23.  MANUFACTURER TO ETCH/STAMP WITH PERMANENT NON-CONDUCTIVE INK | ON SECONDARY SIDE UNLESS OTHERWISE SPECIFIED: | 18.  A TIME DOMAIN REFLECTOMETER REPORT (TDR) FOR EACH IMPEDANCE CONTROLLED LAYER & A CERTIFICATE | 19.  IF PRESENT, ALL BLIND/BURIED VIAS WITH AN ASPECT RATIO <1:1 TO BE PLATED SHUT WITH COPPER WHEN | 20.  FOR VIA FILL INFORMATION REFER TO DRILL CHART: | 24.  MINIMUM DESIGN LINE WIDTH IS .008 INCH. | 25.  MINIMUM DESIGN LINE SPACING IS .008 INCH. | 26.  BOARDS TO BE SHIPPED SINGULATED AFTER FABRICATION PROCESS | SMOOTHEN EDGES AND FREE FROM BURRS AFTER DEPANELIZATION PROCESS | IS ACCEPTABLE, ALL OTHER INSTANCES MUST BE REPORTED. | IF AN INTENTIONAL SHORT REPORT IS SUPPLIED AND DOES NOT MATCH THE FAB DATA THEN | THE PCB SHALL HAVE A VERIFICATION STAMP. | ( )  NON-CONDUCTIVE EPOXY FILL ALL 0.XXXX INCHES DRILLED VIAS | ( )  COPPER FILL ALL 0.XXXX INCHES DRILLED VIAS | ( ) PEMNUTS TO BE INSTALLED BY FABRICATOR | ( ) PEMNUTS NOT TO BE INSTALLED BY FABRICATOR | ( ) NOT APPLICABLE | USED AS VIA-IN-PAD OR AS A STACKED VIA. BLIND/BURIED VIAS WITH AN ASPECT RATIO >1:1 TO BE FILLED | A. UL CODE-FLAMMABILITY RATING FOR THOSE APPROVED MATERIALS(IF APPLICABLE) | B. DATE CODE | C. LOT NUMBER | D. MANUFACTURER LOGO | CAN'T BE PERFORMED BECAUSE THE TRACE LENGTH IS TOO SHORT ON THE OUTER LAYERS AT THE PIN ESCAPES | ADI APPROVAL IS REQUIRED. | OF COMPLIANCE SHALL BE PROVIDED BY VENDOR AT TIME OF SHIPMENT. INSTANCES WHERE TDR TESTING | WITH NON-CONDUCTIVE EPOXY. | TOOLING: | FINISH: | NOTES: | MATERIAL: | TESTING: | MISCELLANEOUS: | DIA MAX | TENTED VIA
User.19: L2 GND | 08-      -07
User.20: L3 GND | 08-      -08
User.35: PER ECR-094468 | B | 28MAY20 | PD
User.37: PAGE 1 OF 5 | TOP SIDE VIEW | VIEW OF SILKSCREEN, PINS, VIAS, | ETCH AND REFERENCE INFORMATION. | TEMPLATE NOTES. | 01.COMPONENTS ARE PLACED ON THIS SIDE. | 02.CONNECTORS P1,P2.P4 & P5 ARE PLACED | ON THIS SIDE OF THE BOARD. | 03.IF THE BOARD NEEDS TO BE INCREASED | IT CAN BE INCREASED IN THE DIRECTION | OF THE ARROWS. | 04.THE BOARD IS SET-UP AS A 4 LAYER | BOARD. MAKE SURE ANY SUBSEQUENT CHANGES, | MANUAL OR AUTOMATIC, DO NOT RESULT IN | ANY UNINTENDED CONSEQUENCES. | 05.THE EXISTING ROUTING CAN BE ALTERED AS | IS ROUTED TO CLOSE THE NETS ON THE | TEMPLATE BOARD.
User.38: PAGE 2 OF 5 | BOTTTOM SIDE VIEW | VIEW OF SILKSCREEN, PINS, VIAS, | ETCH AND REFERENCE INFORMATION. | TEMPLATE NOTES. | 01.COMPONENTS ARE PLACED ON THIS SIDE. | 02.CONNECTORS P3 IS PLACED ON THIS SIDE. THE | OTHER CONNECTORS ARE SOLDERED THIS SIDE. | 03.THE TEMPLATE IS VIEWED LOOKING FROM THE | TOP SIDE OF THE BOARD. THE RESULT IS | THAT TEXT IS MIRRORED. | 04.THE BOARD IS SET-UP AS A 4 LAYER | BOARD. MAKE SURE ANY SUBSEQUENT CHANGES, | MANUAL OR AUTOMATIC, DO NOT RESULT IN | ANY UNINTENDED CONSEQUENCES.
User.39: PAGE 3 OF 5 | PCB FAB SHEET 1 | NCDRILL LEGEND, APPROPRIATE | DETAILS AND OUTLINE DIMENSION NOTES. | 01. EACH TIME THE NC DRILL LEGEND | IS RUN, THE HOLE CHART MUST BE | CHECKED TO ASSURE THE TOLERANCES | & NOTES CORRESPOND TO THE RIGHT | PADSTACKS.
User.40: PAGE 4 OF 5 | PCB FAB SHEET 2 | FABRICATION NOTES. ALTER DEPENDING ON THE | REQUIREMENTS OF THE DESIGN.
User.41: TEMPLATE REVISION HISTORY | TEMPLATE BOARDS FOR EVAL PROVIDE INFORMATION IN THE | 5-VIEW "PDF FORMAT" FOR EVAL ENGINEERING | REFERENCE; ALONG WITH EMBEDDED ALLEGRO | PROPERTIES FOR PCB DESIGN USE. | THEY MAINTAIN A SEPARATE TITLE BLOCK AND PART | NUMBER FOR REVISION TRACKING, INDEPENDENT OF | THE ACTUAL MANUFACTURED DUT-SPECIFIC BOARD | DESIGN. | TEMPLATE BOARDS DISPLAY AS "FILE VIEWS", AND | DUT-SPECIFIC APPLICATION BOARDS ARE | MANUFACTURED FROM ARTWORK "FILM VIEWS"AND NC | DATA. | AND TITLE BLOCK CONTENT IS TRACKING THE | MANUFACTURED BOARD PART NUMBER AND REV, | AND NOT THE TEMPLATE BOARD PART NUMBER AND | REV. | PAGE 5 OF 5 | MAKE SURE THE DUT-SPECIFIC BOARD INFORMATION | REV.A (20APR20) | 1. INITIAL RELEASE. | REV.B (28MAY20) PER ECR-094468 | 1. BRING FILES INTO TEMPLATE FORMAT.
User.45: 1 | FABRICATION | 09-012345-01 | A | FIGURE | SIZE | 10.0 | 15.0 | 45.0 | 50.0 | 125.0 | PLATED | NON-PLATED | FINISHED HOLES IN MILS | ALL UNITS ARE IN MILS | QTY | 172 | 38 | 8 | 4 | TOLERANCE/NOTES
